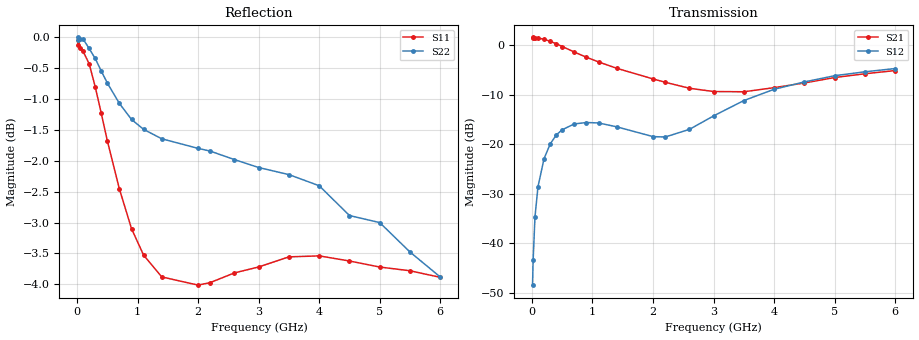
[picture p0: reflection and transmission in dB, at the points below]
! Infineon Technologies  Discrete & RF Semiconductors
! BFS17W
! Si NPN RF Bipolar Junction Transistor in SOT323
! VCE = 5 V  IC = 0.3 mA
! Common Emitter S-Parameters:  August  1999
# GHz  S  MA  R  50
!  f  S11  S21  S12  S22
! GHz  MAG  ANG  MAG  ANG  MAG  ANG  MAG  ANG
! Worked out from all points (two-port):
!   36 points, 10 MHz to 6 GHz, reference 50 ohm
!   highest |S21| = 1.58 dB at 20 MHz (marker M1); lowest = -9.4 dB at 3.5 GHz (marker M2)
!   |S21| within 3 dB of the highest: start of sweep to 708.1 MHz
!   lowest |S11| = -4.0 dB at 2 GHz (marker M3), VSWR 4.40, Z = 11.4 + j2.53 ohm
!   |S11| at or under -10 dB: nowhere
!   |S22| runs from -3.9 to 0.0 dB; largest |S21 - S12| = 1.2
!   S11 on the Smith chart (normalised r, x): 10 MHz: 29, -57; 300 MHz: 0.27, -2.20; 700 MHz: 0.24, -0.83; 1.4 GHz: 0.23, -0.21; 3 GHz: 0.24, +0.38; 6 GHz: 0.52, +1.10
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0.01  0.9857 -1.6  1.187 179.4  0.0038 88.0  0.9999 0.0
0.02  0.9948 -3.6  1.199 177.2  0.0068 90.4  0.9945 -0.9
0.05  0.9798 -8.3  1.19 173.0  0.0185 85.4  0.9972 -2.2
0.1  0.9741 -16.4  1.179 166.2  0.0374 80.7  0.9969 -4.5
0.2  0.9521 -32.9  1.151 152.1  0.0716 70.3  0.9794 -8.8
0.3  0.9121 -48.4  1.094 139.2  0.1004 61.3  0.9613 -12.6
0.4  0.8683 -62.6  1.036 127.0  0.1238 52.6  0.9392 -16.2
0.5  0.8247 -75.7  0.97 116.4  0.1404 45.8  0.9184 -19.2
0.7  0.7536 -98.9  0.853 98.0  0.1606 35.0  0.884 -24.8
0.9  0.6999 -118.3  0.756 83.4  0.166 27.0  0.858 -29.9
1.1  0.6661 -134.4  0.678 71.2  0.1643 22.0  0.8422 -34.9
1.4  0.6396 -154.8  0.585 57.0  0.1502 18.3  0.8276 -42.7
2  0.6299 173.9  0.457 39.0  0.1197 30.3  0.8129 -59.5
2.2  0.6329 165.5  0.423 35.5  0.1185 40.0  0.8088 -65.3
2.6  0.6444 150.1  0.368 32.1  0.1415 58.8  0.7961 -77.4
3  0.6516 136.2  0.341 33.7  0.1935 67.4  0.7844 -89.1
3.5  0.664 121.3  0.339 38.3  0.2764 67.4  0.7741 -104.6
4  0.6652 108.7  0.373 41.2  0.3592 61.5  0.7582 -121.2
4.5  0.6589 98.0  0.416 40.7  0.4262 54.1  0.7172 -136.6
5  0.6515 89.9  0.472 37.3  0.4923 46.8  0.7078 -150.4
5.5  0.647 82.9  0.515 33.1  0.5392 39.5  0.67 -164.5
6  0.6391 77.5  0.555 28.6  0.5813 32.9  0.6395 -176.7
